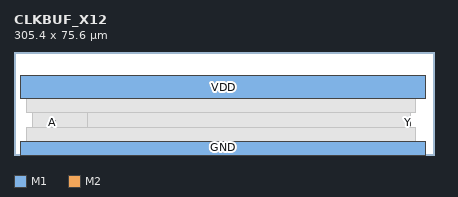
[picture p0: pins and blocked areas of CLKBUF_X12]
MACRO CLKBUF_X12
  CLASS CORE ;
  ORIGIN 0 0 ;
  SIZE 305.400 BY 75.600 ;
  SYMMETRY X Y ;
  SITE TR1um_access_site ;
  PIN VDD
    DIRECTION INOUT ;
    USE POWER ;
    PORT
      LAYER M1 ;
        RECT 5.000 41.000 299.100 57.600 ;
    END
  END VDD
  PIN GND
    DIRECTION INOUT ;
    USE GROUND ;
    PORT
      LAYER M1 ;
        RECT 5.000 0.000 299.100 9.800 ;
    END
  END GND
  PIN A
    DIRECTION INPUT ;
    USE SIGNAL ;
    PORT
      LAYER M2 ;
        RECT 26.600 21.600 30.000 25.000 ;
    END
  END A
  PIN Y
    DIRECTION OUTPUT ;
    USE SIGNAL ;
    PORT
      LAYER M2 ;
        RECT 285.100 21.600 288.500 25.000 ;
    END
  END Y
  OBS
    LAYER M1 ;
      RECT 19.100 16.400 41.700 34.400 ;
    LAYER M1 ;
      RECT 13.100 6.400 281.700 51.200 ;
    LAYER M1 ;
      RECT 53.100 6.400 288.500 51.200 ;
    LAYER V1 ;
      RECT 8.900 4.000 291.900 20.200 ;
    LAYER V1 ;
      RECT 8.900 30.600 291.900 53.600 ;
    LAYER V1 ;
      RECT 164.300 0.000 167.300 2.800 ;
    LAYER V1 ;
      RECT 169.800 0.000 172.800 2.800 ;
    LAYER V1 ;
      RECT 175.300 0.000 178.300 2.800 ;
    LAYER V1 ;
      RECT 180.800 0.000 183.800 2.800 ;
    LAYER V1 ;
      RECT 186.300 0.000 189.300 2.800 ;
    LAYER V1 ;
      RECT 191.800 0.000 194.800 2.800 ;
    LAYER V1 ;
      RECT 197.300 0.000 200.300 2.800 ;
    LAYER V1 ;
      RECT 202.800 0.000 205.800 2.800 ;
    LAYER V1 ;
      RECT 208.300 0.000 211.300 2.800 ;
    LAYER V1 ;
      RECT 213.800 0.000 216.800 2.800 ;
    LAYER V1 ;
      RECT 219.300 0.000 222.300 2.800 ;
    LAYER V1 ;
      RECT 224.800 0.000 227.800 2.800 ;
    LAYER V1 ;
      RECT 230.300 0.000 233.300 2.800 ;
    LAYER V1 ;
      RECT 235.800 0.000 238.800 2.800 ;
    LAYER V1 ;
      RECT 241.300 0.000 244.300 2.800 ;
    LAYER V1 ;
      RECT 246.800 0.000 249.800 2.800 ;
    LAYER V1 ;
      RECT 252.300 0.000 255.300 2.800 ;
    LAYER V1 ;
      RECT 257.800 0.000 260.800 2.800 ;
    LAYER V1 ;
      RECT 263.300 0.000 266.300 2.800 ;
    LAYER V1 ;
      RECT 268.800 0.000 271.800 2.800 ;
    LAYER V1 ;
      RECT 274.300 0.000 277.300 2.800 ;
    LAYER V1 ;
      RECT 279.800 0.000 282.800 2.800 ;
    LAYER V1 ;
      RECT 285.300 0.000 288.300 2.800 ;
    LAYER V1 ;
      RECT 290.800 0.000 293.800 2.800 ;
    LAYER V1 ;
      RECT 296.300 0.000 299.300 2.800 ;
    LAYER V1 ;
      RECT 153.300 0.000 156.300 2.800 ;
    LAYER V1 ;
      RECT 286.100 22.600 287.500 24.000 ;
    LAYER V1 ;
      RECT 158.800 0.000 161.800 2.800 ;
    LAYER V1 ;
      RECT 153.300 54.800 156.300 57.800 ;
    LAYER V1 ;
      RECT 158.800 54.800 161.800 57.800 ;
    LAYER V1 ;
      RECT 164.300 54.800 167.300 57.800 ;
    LAYER V1 ;
      RECT 169.800 54.800 172.800 57.800 ;
    LAYER V1 ;
      RECT 175.300 54.800 178.300 57.800 ;
    LAYER V1 ;
      RECT 180.800 54.800 183.800 57.800 ;
    LAYER V1 ;
      RECT 186.300 54.800 189.300 57.800 ;
    LAYER V1 ;
      RECT 191.800 54.800 194.800 57.800 ;
    LAYER V1 ;
      RECT 197.300 54.800 200.300 57.800 ;
    LAYER V1 ;
      RECT 202.800 54.800 205.800 57.800 ;
    LAYER V1 ;
      RECT 208.300 54.800 211.300 57.800 ;
    LAYER V1 ;
      RECT 213.800 54.800 216.800 57.800 ;
    LAYER V1 ;
      RECT 219.300 54.800 222.300 57.800 ;
    LAYER V1 ;
      RECT 224.800 54.800 227.800 57.800 ;
    LAYER V1 ;
      RECT 230.300 54.800 233.300 57.800 ;
    LAYER V1 ;
      RECT 235.800 54.800 238.800 57.800 ;
    LAYER V1 ;
      RECT 241.300 54.800 244.300 57.800 ;
    LAYER V1 ;
      RECT 246.800 54.800 249.800 57.800 ;
    LAYER V1 ;
      RECT 252.300 54.800 255.300 57.800 ;
    LAYER V1 ;
      RECT 257.800 54.800 260.800 57.800 ;
    LAYER V1 ;
      RECT 263.300 54.800 266.300 57.800 ;
    LAYER V1 ;
      RECT 268.800 54.800 271.800 57.800 ;
    LAYER V1 ;
      RECT 274.300 54.800 277.300 57.800 ;
    LAYER V1 ;
      RECT 279.800 54.800 282.800 57.800 ;
    LAYER V1 ;
      RECT 285.300 54.800 288.300 57.800 ;
    LAYER V1 ;
      RECT 290.800 54.800 293.800 57.800 ;
    LAYER V1 ;
      RECT 296.300 54.800 299.300 57.800 ;
    LAYER V1 ;
      RECT 15.800 0.000 18.800 2.800 ;
    LAYER V1 ;
      RECT 4.800 54.800 7.800 57.800 ;
    LAYER V1 ;
      RECT 10.300 54.800 13.300 57.800 ;
    LAYER V1 ;
      RECT 15.800 54.800 18.800 57.800 ;
    LAYER V1 ;
      RECT 21.300 54.800 24.300 57.800 ;
    LAYER V1 ;
      RECT 26.800 54.800 29.800 57.800 ;
    LAYER V1 ;
      RECT 32.300 54.800 35.300 57.800 ;
    LAYER V1 ;
      RECT 37.800 54.800 40.800 57.800 ;
    LAYER V1 ;
      RECT 43.300 54.800 46.300 57.800 ;
    LAYER V1 ;
      RECT 48.800 54.800 51.800 57.800 ;
    LAYER V1 ;
      RECT 54.300 54.800 57.300 57.800 ;
    LAYER V1 ;
      RECT 59.800 54.800 62.800 57.800 ;
    LAYER V1 ;
      RECT 65.300 54.800 68.300 57.800 ;
    LAYER V1 ;
      RECT 70.800 54.800 73.800 57.800 ;
    LAYER V1 ;
      RECT 76.300 54.800 79.300 57.800 ;
    LAYER V1 ;
      RECT 81.800 54.800 84.800 57.800 ;
    LAYER V1 ;
      RECT 87.300 54.800 90.300 57.800 ;
    LAYER V1 ;
      RECT 92.800 54.800 95.800 57.800 ;
    LAYER V1 ;
      RECT 98.300 54.800 101.300 57.800 ;
    LAYER V1 ;
      RECT 103.800 54.800 106.800 57.800 ;
    LAYER V1 ;
      RECT 109.300 54.800 112.300 57.800 ;
    LAYER V1 ;
      RECT 114.800 54.800 117.800 57.800 ;
    LAYER V1 ;
      RECT 120.300 54.800 123.300 57.800 ;
    LAYER V1 ;
      RECT 125.800 54.800 128.800 57.800 ;
    LAYER V1 ;
      RECT 131.300 54.800 134.300 57.800 ;
    LAYER V1 ;
      RECT 136.800 54.800 139.800 57.800 ;
    LAYER V1 ;
      RECT 142.300 54.800 145.300 57.800 ;
    LAYER V1 ;
      RECT 147.800 54.800 150.800 57.800 ;
    LAYER V1 ;
      RECT 21.300 0.000 24.300 2.800 ;
    LAYER V1 ;
      RECT 26.800 0.000 29.800 2.800 ;
    LAYER V1 ;
      RECT 32.300 0.000 35.300 2.800 ;
    LAYER V1 ;
      RECT 37.800 0.000 40.800 2.800 ;
    LAYER V1 ;
      RECT 43.300 0.000 46.300 2.800 ;
    LAYER V1 ;
      RECT 48.800 0.000 51.800 2.800 ;
    LAYER V1 ;
      RECT 54.300 0.000 57.300 2.800 ;
    LAYER V1 ;
      RECT 59.800 0.000 62.800 2.800 ;
    LAYER V1 ;
      RECT 65.300 0.000 68.300 2.800 ;
    LAYER V1 ;
      RECT 70.800 0.000 73.800 2.800 ;
    LAYER V1 ;
      RECT 76.300 0.000 79.300 2.800 ;
    LAYER V1 ;
      RECT 81.800 0.000 84.800 2.800 ;
    LAYER V1 ;
      RECT 87.300 0.000 90.300 2.800 ;
    LAYER V1 ;
      RECT 92.800 0.000 95.800 2.800 ;
    LAYER V1 ;
      RECT 98.300 0.000 101.300 2.800 ;
    LAYER V1 ;
      RECT 103.800 0.000 106.800 2.800 ;
    LAYER V1 ;
      RECT 109.300 0.000 112.300 2.800 ;
    LAYER V1 ;
      RECT 114.800 0.000 117.800 2.800 ;
    LAYER V1 ;
      RECT 120.300 0.000 123.300 2.800 ;
    LAYER V1 ;
      RECT 125.800 0.000 128.800 2.800 ;
    LAYER V1 ;
      RECT 131.300 0.000 134.300 2.800 ;
    LAYER V1 ;
      RECT 136.800 0.000 139.800 2.800 ;
    LAYER V1 ;
      RECT 142.300 0.000 145.300 2.800 ;
    LAYER V1 ;
      RECT 147.800 0.000 150.800 2.800 ;
    LAYER V1 ;
      RECT 4.800 0.000 7.800 2.800 ;
    LAYER V1 ;
      RECT 27.600 22.600 29.000 24.000 ;
    LAYER V1 ;
      RECT 10.300 0.000 13.300 2.800 ;
  END
END CLKBUF_X12
